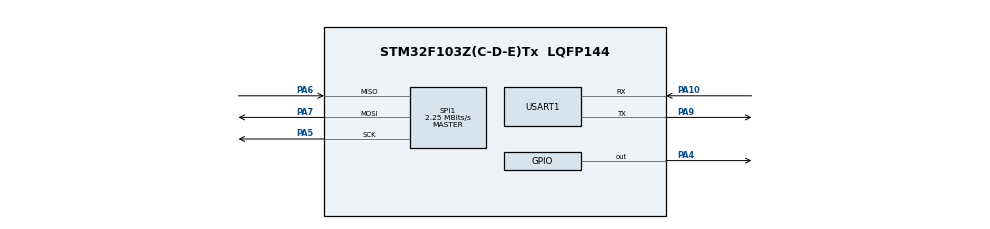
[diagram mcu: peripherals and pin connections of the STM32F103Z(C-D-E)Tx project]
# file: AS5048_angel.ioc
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Mcu.Family=STM32F1
Mcu.Name=STM32F103Z(C-D-E)Tx
Mcu.Package=LQFP144
NVIC.PriorityGroup=NVIC_PRIORITYGROUP_4
OSC_IN.Mode=HSE-External-Oscillator
OSC_IN.Signal=RCC_OSC_IN
OSC_OUT.Mode=HSE-External-Oscillator
OSC_OUT.Signal=RCC_OSC_OUT
PA10.Mode=Asynchronous
PA10.Signal=USART1_RX
PA13.Mode=Serial_Wire
PA13.Signal=SYS_JTMS-SWDIO
PA14.Mode=Serial_Wire
PA14.Signal=SYS_JTCK-SWCLK
PA4.GPIO_Speed=GPIO_SPEED_FREQ_HIGH
PA4.PinState=GPIO_PIN_SET
PA4.Signal=GPIO_Output
PA5.Mode=Full_Duplex_Master
PA5.Signal=SPI1_SCK
PA6.Mode=Full_Duplex_Master
PA6.Signal=SPI1_MISO
PA7.Mode=Full_Duplex_Master
PA7.Signal=SPI1_MOSI
PA9.Mode=Asynchronous
PA9.Signal=USART1_TX
ProjectManager.HeapSize=0x200
ProjectManager.StackSize=0x400
ProjectManager.TargetToolchain=MDK-ARM V5.32
RCC.AHBFreq_Value=72000000
RCC.APB1CLKDivider=RCC_HCLK_DIV2
RCC.APB1Freq_Value=36000000
RCC.APB1TimFreq_Value=72000000
RCC.APB2Freq_Value=72000000
RCC.APB2TimFreq_Value=72000000
RCC.HCLKFreq_Value=72000000
RCC.PLLMUL=RCC_PLL_MUL9
RCC.PLLSourceVirtual=RCC_PLLSOURCE_HSE
RCC.SYSCLKFreq_VALUE=72000000
RCC.SYSCLKSource=RCC_SYSCLKSOURCE_PLLCLK
RCC.USBFreq_Value=72000000
SPI1.BaudRatePrescaler=SPI_BAUDRATEPRESCALER_32
SPI1.CLKPhase=SPI_PHASE_2EDGE
SPI1.CalculateBaudRate=2.25 MBits/s
SPI1.DataSize=SPI_DATASIZE_16BIT
SPI1.Direction=SPI_DIRECTION_2LINES
SPI1.Mode=SPI_MODE_MASTER
SPI1.VirtualType=VM_MASTER
USART1.VirtualMode=VM_ASYNC
board=custom

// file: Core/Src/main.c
/* USER CODE BEGIN Header */
/**
  ******************************************************************************
  * @file           : main.c
  * @brief          : Main program body
  ******************************************************************************
  * @attention
  *
  * Copyright (c) 2026 STMicroelectronics.
  * All rights reserved.
  *
  * This software is licensed under terms that can be found in the LICENSE file
  * in the root directory of this software component.
  * If no LICENSE file comes with this software, it is provided AS-IS.
  *
  ******************************************************************************
  */
/* USER CODE END Header */
#include "main.h"
#include "spi.h"
#include "usart.h"
#include "gpio.h"

/* USER CODE BEGIN Includes */
#include "as5048a.h"
#include "servo.h"
/* USER CODE END Includes */

//SPI_HandleTypeDef hspi1;

//UART_HandleTypeDef huart1;

void SystemClock_Config(void);

//static void MX_GPIO_Init(void);
//static void MX_SPI1_Init(void);
//static void MX_USART1_UART_Init(void);

/* USER CODE BEGIN 0 */

uint8_t  TXD[6] = {0};

/*
 * 固定软件零点：舵机/磁铁处于机械 0° 时的 AS5048A 原始角度计数。
 * 标定方法：临时发送/观察原始角度，机械 0° 时读出的 0~16383 数值填入此处。
 * 该值一旦填好，程序每次上电都使用同一个零点，不再执行上电采零。
 */
//#define ENCODER_ZERO_RAW  (14479u) /* 1520 us 舵机中位时标定的 AS5048A 原始值 */
#define ENCODER_ZERO_RAW  (14485u)
#define ENCODER_DIRECTION (+1) /* 若舵机正角使原始值减小，改为 -1 */

/* ---- 舵机校准扫描参数（单位 us） -------------------------------------------- */
#define CAL_PULSE_MIN_US  1180u
#define CAL_PULSE_MAX_US  1846u
#define CAL_PULSE_STEP_US 50u
#define CAL_DWELL_MS      300u

/* ---- 采样平均（每步多采几次取平均，让数据更稳） ---- */
#define SAMPLE_N         4         /* 每步采样次数 */
#define SAMPLE_GAP_MS    2         /* 相邻采样间隔 */

/* USER CODE END 0 */

int main(void)
{

  /* MCU Configuration--------------------------------------------------------*/

  /* Reset of all peripherals, Initializes the Flash interface and the Systick. */
  HAL_Init();

  /* Configure the system clock */
  SystemClock_Config();

  /* Initialize all configured peripherals */
  MX_GPIO_Init();
  MX_SPI1_Init();
  MX_USART1_UART_Init();
  /* USER CODE BEGIN 2 */
	AS5048A_Init();
	Servo_Init();               /* 舵机先输出中性脉宽，回到 0° */

	TXD[0] = 0x55;              /* 帧头 */

	/* 舵机先回机械中立位，但零点使用上面的固定标定值 */
	Servo_SetPulseUs(SERVO_PULSE_MID_US);
	HAL_Delay(1000);

  /* USER CODE END 2 */

  /* Infinite loop */
  while (1)
  {

    /* USER CODE BEGIN 3 */
		static uint16_t last = 0;                     /* 上次有效原始角度 */
		static uint16_t pulse_us = CAL_PULSE_MIN_US;
		static int8_t pulse_step = 1;

		AS5048A_Status_t status = AS5048A_OK;
		int32_t acc = 0;
		uint8_t ok = 0;
		uint8_t i;

		/* 1. 直接扫描舵机控制脉宽，避免角度换算影响全行程测试。 */
		Servo_SetPulseUs(pulse_us);
		HAL_Delay(CAL_DWELL_MS);

		/* 2. 连续采 SAMPLE_N 次取平均，滤除抖动 */
		for (i = 0; i < SAMPLE_N; i++)
		{
			AS5048A_AngleResult_t r = AS5048A_ReadAngle();
			if (r.status == AS5048A_OK) { acc += r.angle; ok++; }
			else                        { status = r.status; }   /* 记录最近一次错误 */
			HAL_Delay(SAMPLE_GAP_MS);
		}
		if (ok)
		{
			last   = (uint16_t)(acc / ok);
			status = AS5048A_OK;
		}
		/* 全部采样失败则沿用 last（上一次有效角），status 保持错误类型 */

		int32_t rel = ((int32_t)last - (int32_t)ENCODER_ZERO_RAW) * ENCODER_DIRECTION;
		if (rel > 8192) rel -= 16384;
		else if (rel <= -8192) rel += 16384;
		int16_t meas_x100 = (int16_t)(rel * 36000 / 16384);

		/* 3. 校准帧：0x55 | 状态 | 脉宽 us(16 位) | 编码器原始角(16 位)。 */
		TXD[1] = 0xAA + (uint8_t)status;
		TXD[2] = (uint8_t)(pulse_us >> 8);
		TXD[3] = (uint8_t)(pulse_us & 0xFFu);
		TXD[4] = (uint8_t)((uint16_t)meas_x100 >> 8);
		TXD[5] = (uint8_t)(meas_x100 & 0xFFu);

		(void)HAL_UART_Transmit(&huart1, TXD, 6, 0xFFFF);

		/* 4. 到 500/2500 us 边界时反向，形成全行程脉宽三角波。 */
		if (pulse_us >= CAL_PULSE_MAX_US) pulse_step = -1;
		else if (pulse_us <= CAL_PULSE_MIN_US) pulse_step = 1;
		pulse_us = (uint16_t)((int32_t)pulse_us +
		                    pulse_step * (int32_t)CAL_PULSE_STEP_US);
    /* USER CODE END 3 */
  }
}

//void SystemClock_Config(void)
//{
//  RCC_OscInitTypeDef RCC_OscInitStruct = {0};
//  RCC_ClkInitTypeDef RCC_ClkInitStruct = {0};

//  /** Initializes the RCC Oscillators according to the specified parameters
//  * in the RCC_OscInitTypeDef structure.
//  */
//  RCC_OscInitStruct.OscillatorType = RCC_OSCILLATORTYPE_HSE;
//  RCC_OscInitStruct.HSEState = RCC_HSE_ON;
//  RCC_OscInitStruct.HSEPredivValue = RCC_HSE_PREDIV_DIV1;
//  RCC_OscInitStruct.HSIState = RCC_HSI_ON;
//  RCC_OscInitStruct.PLL.PLLState = RCC_PLL_ON;
//  RCC_OscInitStruct.PLL.PLLSource = RCC_PLLSOURCE_HSE;
//  RCC_OscInitStruct.PLL.PLLMUL = RCC_PLL_MUL9;
//  if (HAL_RCC_OscConfig(&RCC_OscInitStruct) != HAL_OK)
//  {
//    Error_Handler();
//  }

//  /** Initializes the CPU, AHB and APB buses clocks
//  */
//  RCC_ClkInitStruct.ClockType = RCC_CLOCKTYPE_HCLK|RCC_CLOCKTYPE_SYSCLK
//                              |RCC_CLOCKTYPE_PCLK1|RCC_CLOCKTYPE_PCLK2;
//  RCC_ClkInitStruct.SYSCLKSource = RCC_SYSCLKSOURCE_PLLCLK;
//  RCC_ClkInitStruct.AHBCLKDivider = RCC_SYSCLK_DIV1;
//  RCC_ClkInitStruct.APB1CLKDivider = RCC_HCLK_DIV2;
//  RCC_ClkInitStruct.APB2CLKDivider = RCC_HCLK_DIV1;

//  if (HAL_RCC_ClockConfig(&RCC_ClkInitStruct, FLASH_LATENCY_2) != HAL_OK)
//  {
//    Error_Handler();
//  }
//}

void SystemClock_Config(void)
{
  RCC_OscInitTypeDef RCC_OscInitStruct = {0};
  RCC_ClkInitTypeDef RCC_ClkInitStruct = {0};

  RCC_OscInitStruct.OscillatorType = RCC_OSCILLATORTYPE_HSI;
  RCC_OscInitStruct.HSIState = RCC_HSI_ON;
  RCC_OscInitStruct.HSICalibrationValue = RCC_HSICALIBRATION_DEFAULT;
  RCC_OscInitStruct.PLL.PLLState = RCC_PLL_NONE;
  if (HAL_RCC_OscConfig(&RCC_OscInitStruct) != HAL_OK)
  {
    while (1) {}
  }

  RCC_ClkInitStruct.ClockType = RCC_CLOCKTYPE_HCLK | RCC_CLOCKTYPE_SYSCLK
                              | RCC_CLOCKTYPE_PCLK1 | RCC_CLOCKTYPE_PCLK2;
  RCC_ClkInitStruct.SYSCLKSource = RCC_SYSCLKSOURCE_HSI;
  RCC_ClkInitStruct.AHBCLKDivider = RCC_SYSCLK_DIV1;
  RCC_ClkInitStruct.APB1CLKDivider = RCC_HCLK_DIV1;
  RCC_ClkInitStruct.APB2CLKDivider = RCC_HCLK_DIV1;
  if (HAL_RCC_ClockConfig(&RCC_ClkInitStruct, FLASH_LATENCY_0) != HAL_OK)
  {
    while (1) {}
  }
}

void Error_Handler(void)
{
  __disable_irq();
  while (1)
  {
  }
}
